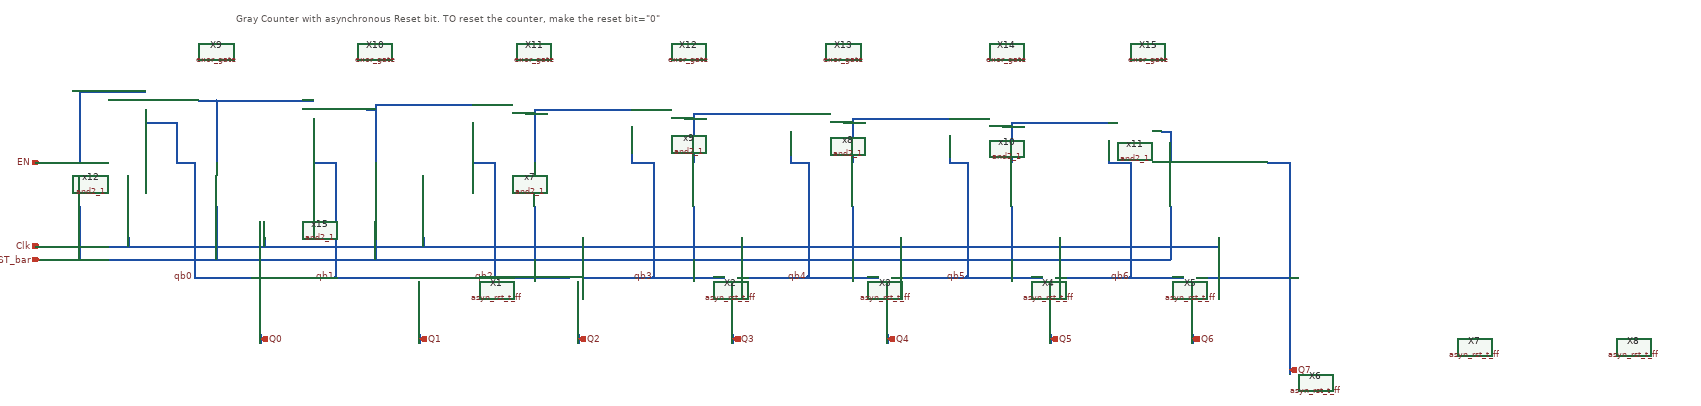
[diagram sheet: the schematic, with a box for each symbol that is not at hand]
v {xschem version=2.9.9 file_version=1.2 }
G {}
K {}
V {}
S {}
E {}
T {Gray Counter with asynchronous Reset bit. TO reset the counter, make the reset bit="0"} -4445 652.5 0 0 0.4 0.4 {}
N -3480 1180 -2370 1180 { lab=Clk}
N -4900 1180 -4820 1180 { lab=Clk}
N -4820 1180 -3710 1180 { lab=Clk}
N -4390 1380 -4390 1400 { lab=Q0}
N -2220 1160 -2220 1180 { lab=Clk}
N -2580 1160 -2580 1180 { lab=Clk}
N -2940 1160 -2940 1180 { lab=Clk}
N -3300 1160 -3300 1180 { lab=Clk}
N -3660 1160 -3660 1180 { lab=Clk}
N -4020 1160 -4020 1180 { lab=Clk}
N -4690 1160 -4690 1180 { lab=Clk}
N -4380 1160 -4380 1180 { lab=Clk}
N -4900 990 -4800 990 { lab=EN}
N -4490 850 -4490 990 { lab=#net1}
N -4490 850 -4270 850 { lab=#net1}
N -4130 860 -4130 990 { lab=#net2}
N -4130 860 -3910 860 { lab=#net2}
N -3770 870 -3770 990 { lab=#net3}
N -3770 870 -3550 870 { lab=#net3}
N -3410 880 -3410 990 { lab=#net4}
N -3410 880 -3190 880 { lab=#net4}
N -3050 890 -2850 890 { lab=#net5}
N -2850 890 -2830 890 { lab=#net5}
N -3050 890 -3050 990 { lab=#net5}
N -2690 900 -2690 990 { lab=#net6}
N -2690 900 -2470 900 { lab=#net6}
N -2110 990 -2060 990 { lab=Q7}
N -2060 990 -2060 1470 { lab=Q7}
N -4540 990 -4540 1250 { lab=qb0}
N -4270 990 -4220 990 { lab=qb1}
N -4220 990 -4220 1250 { lab=qb1}
N -3910 990 -3860 990 { lab=qb2}
N -3860 990 -3860 1250 { lab=qb2}
N -3550 990 -3500 990 { lab=qb3}
N -3500 990 -3500 1250 { lab=qb3}
N -3710 1180 -3480 1180 { lab=Clk}
N -2370 1180 -2220 1180 { lab=Clk}
N -3190 990 -3150 990 { lab=qb4}
N -3150 990 -3150 1250 { lab=qb4}
N -2830 990 -2790 990 { lab=qb5}
N -2790 990 -2790 1250 { lab=qb5}
N -2470 990 -2420 990 { lab=qb6}
N -2420 990 -2420 1250 { lab=qb6}
N -4370 1250 -4220 1250 { lab=qb1}
N -4010 1250 -3860 1250 { lab=qb2}
N -3860 1250 -3710 1250 { lab=qb2}
N -3650 1250 -3500 1250 { lab=qb3}
N -3500 1250 -3370 1250 { lab=qb3}
N -3300 1250 -3150 1250 { lab=qb4}
N -2950 1250 -2790 1250 { lab=qb5}
N -2580 1250 -2420 1250 { lab=qb6}
N -2420 1250 -2320 1250 { lab=qb6}
N -2260 1250 -2060 1250 { lab=Q7}
N -4540 1250 -4410 1250 { lab=qb0}
N -4220 1250 -4050 1250 { lab=qb1}
N -3710 1250 -3690 1250 { lab=qb2}
N -3370 1250 -3340 1250 { lab=qb3}
N -3150 1250 -2990 1250 { lab=qb4}
N -2790 1250 -2620 1250 { lab=qb5}
N -2320 1250 -2300 1250 { lab=qb6}
N -4270 890 -4270 990 { lab=qb1}
N -4150 870 -4130 870 { lab=#net2}
N -3910 900 -3910 990 { lab=qb2}
N -3790 880 -3770 880 { lab=#net3}
N -3550 910 -3550 990 { lab=qb3}
N -3430 890 -3410 890 { lab=#net4}
N -3190 920 -3190 990 { lab=qb4}
N -3070 900 -3050 900 { lab=#net5}
N -2830 930 -2830 990 { lab=qb5}
N -2710 910 -2690 910 { lab=#net6}
N -2470 940 -2470 990 { lab=qb6}
N -2350 920 -2330 920 { lab=#net7}
N -2330 920 -2330 990 { lab=#net7}
N -4800 830 -4800 990 { lab=EN}
N -4800 830 -4650 830 { lab=EN}
N -4650 870 -4650 900 { lab=qb0}
N -4650 900 -4580 900 { lab=qb0}
N -4580 900 -4580 990 { lab=qb0}
N -4580 990 -4540 990 { lab=qb0}
N -4530 850 -4490 850 { lab=#net1}
N -4900 1210 -2330 1210 { lab=RST_bar}
N -2330 1090 -2330 1210 { lab=RST_bar}
N -2690 1090 -2690 1210 { lab=RST_bar}
N -3050 1090 -3050 1200 { lab=RST_bar}
N -3050 1200 -3050 1210 { lab=RST_bar}
N -3410 1090 -3410 1210 { lab=RST_bar}
N -3770 1090 -3770 1210 { lab=RST_bar}
N -4130 1090 -4130 1210 { lab=RST_bar}
N -4490 1090 -4490 1210 { lab=RST_bar}
N -4800 1090 -4800 1210 { lab=RST_bar}
N -4380 1250 -4370 1250 { lab=qb1}
N -4030 1380 -4030 1400 { lab=Q1}
N -4020 1250 -4010 1250 { lab=qb2}
N -3670 1380 -3670 1400 { lab=Q2}
N -3660 1250 -3650 1250 { lab=qb3}
N -3320 1380 -3320 1400 { lab=Q3}
N -3310 1250 -3300 1250 { lab=qb4}
N -2970 1380 -2970 1400 { lab=Q4}
N -2960 1250 -2950 1250 { lab=qb5}
N -2600 1380 -2600 1400 { lab=Q5}
N -2590 1250 -2580 1250 { lab=qb6}
N -2280 1380 -2280 1400 { lab=Q0}
N -2270 1250 -2260 1250 { lab=Q7}
C {devices/ipin.sym} -4890 1180 0 0 {name=p11 lab=Clk}
C {devices/ipin.sym} -4890 990 0 0 {name=p12 lab=EN}
C {devices/opin.sym} -4390 1390 1 0 {name=p13 lab=Q0}
C {devices/opin.sym} -2060 1460 1 0 {name=p20 lab=Q7}
C {devices/lab_pin.sym} -4540 1250 3 0 {name=l8 sig_type=std_logic lab=qb0}
C {devices/lab_pin.sym} -4220 1250 3 0 {name=l9 sig_type=std_logic lab=qb1}
C {devices/lab_pin.sym} -3860 1250 3 0 {name=l10 sig_type=std_logic lab=qb2}
C {devices/lab_pin.sym} -3500 1250 3 0 {name=l11 sig_type=std_logic lab=qb3}
C {devices/lab_pin.sym} -3150 1250 3 0 {name=l12 sig_type=std_logic lab=qb4}
C {devices/lab_pin.sym} -2790 1250 3 0 {name=l13 sig_type=std_logic lab=qb5}
C {devices/lab_pin.sym} -2420 1250 3 0 {name=l14 sig_type=std_logic lab=qb6}
C {sky130_stdcells/and2_1.sym} -4210 870 0 0 {name=x15 VGND=GND VNB=GND VPB=VDD VPWR=VDD prefix=sky130_fd_sc_lp__ }
C {sky130_stdcells/and2_1.sym} -3850 880 0 0 {name=x7 VGND=GND VNB=GND VPB=VDD VPWR=VDD prefix=sky130_fd_sc_lp__ }
C {sky130_stdcells/and2_1.sym} -3130 900 0 0 {name=x8 VGND=GND VNB=GND VPB=VDD VPWR=VDD prefix=sky130_fd_sc_lp__ }
C {sky130_stdcells/and2_1.sym} -3490 890 0 0 {name=x9 VGND=GND VNB=GND VPB=VDD VPWR=VDD prefix=sky130_fd_sc_lp__  }
C {sky130_stdcells/and2_1.sym} -2770 910 0 0 {name=x10 VGND=GND VNB=GND VPB=VDD VPWR=VDD prefix=sky130_fd_sc_lp__ }
C {sky130_stdcells/and2_1.sym} -2410 920 0 0 {name=x11 VGND=GND VNB=GND VPB=VDD VPWR=VDD prefix=sky130_fd_sc_lp__ }
C {sky130_stdcells/and2_1.sym} -4590 850 0 0 {name=x12 VGND=GND VNB=GND VPB=VDD VPWR=VDD prefix=sky130_fd_sc_lp__ }
C {T_flip_flop/asyn_rst_t_ff.sym} -3750 1410 0 0 {name=X1}
C {T_flip_flop/asyn_rst_t_ff.sym} -3440 1410 0 0 {name=X2}
C {T_flip_flop/asyn_rst_t_ff.sym} -3080 1410 0 0 {name=X3}
C {T_flip_flop/asyn_rst_t_ff.sym} -2720 1410 0 0 {name=X4}
C {T_flip_flop/asyn_rst_t_ff.sym} -2360 1410 0 0 {name=X5}
C {T_flip_flop/asyn_rst_t_ff.sym} -2000 1410 0 0 {name=X6}
C {T_flip_flop/asyn_rst_t_ff.sym} -1640 1410 0 0 {name=X7}
C {T_flip_flop/asyn_rst_t_ff.sym} -1280 1410 0 0 {name=X8}
C {devices/ipin.sym} -4890 1210 0 0 {name=p22 lab=RST_bar}
C {exor_gate/exor_gate.sym} -4490 740 1 0 {name=X9}
C {devices/opin.sym} -4030 1390 1 0 {name=p1 lab=Q1}
C {exor_gate/exor_gate.sym} -4130 740 1 0 {name=X10}
C {devices/opin.sym} -3670 1390 1 0 {name=p2 lab=Q2}
C {exor_gate/exor_gate.sym} -3770 740 1 0 {name=X11}
C {devices/opin.sym} -3320 1390 1 0 {name=p3 lab=Q3}
C {exor_gate/exor_gate.sym} -3420 740 1 0 {name=X12}
C {devices/opin.sym} -2970 1390 1 0 {name=p4 lab=Q4}
C {exor_gate/exor_gate.sym} -3070 740 1 0 {name=X13}
C {devices/opin.sym} -2600 1390 1 0 {name=p5 lab=Q5}
C {exor_gate/exor_gate.sym} -2700 740 1 0 {name=X14}
C {devices/opin.sym} -2280 1390 1 0 {name=p6 lab=Q6}
C {exor_gate/exor_gate.sym} -2380 740 1 0 {name=X15}
